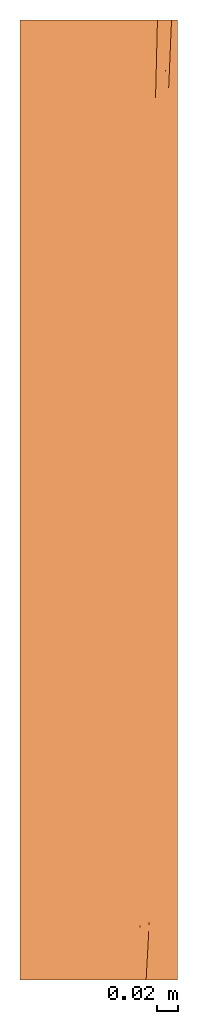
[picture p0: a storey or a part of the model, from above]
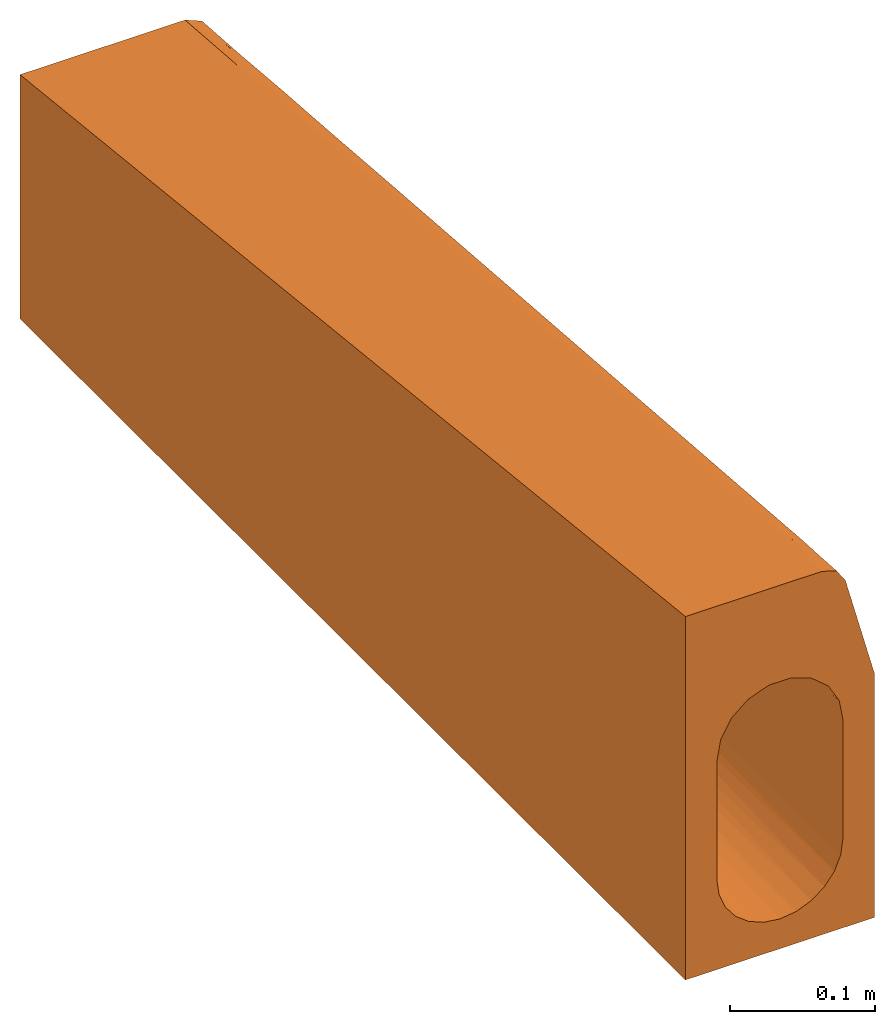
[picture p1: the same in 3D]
Properties of the parts of a building model (IFC2X3)

# File
Description: ViewDefinition [CoordinationView]
File name: 7966 - LH drop kerb - 915mm LG.ifc
Time: 2013-09-12T12:44:50
Written by: Autodesk Revit 2013
Made in: 20120221_2030(x64)

# IfcProject, Project Number
LongName: Project Name; Phase: Project Status

# IfcSite, Default
RefLatitude: 42, 21, 30, 344238; RefLongitude: -71, -3, -35, -194702; RefElevation: 0 mm

# IfcBuilding
Pset_BuildingCommon - NumberOfStoreys: 2
Other - Project Issue Date: Issue Date; Project Status: Project Status; Project Name: Project Name; Client Name: Owner; Project Number: Project Number; Project Address: Enter address here

# IfcBuildingStorey (2)
Constraints - Elevation Base: 0
Graphics - Line Pattern: Center; Color: 0; Symbol at End 2 Default: yes; Symbol at End 1 Default: no; Symbol: M_Level Head - Circle: M_Level Head - Circle; Line Weight: 1
Identity Data - Building Story: yes; Structural: no
Dimensions - Computation Height: 0 mm
Name | LongName = Name | Elevation (mm) = Constraints, Elevation (mm)
T.O. Fnd. Wall | T.O. Fnd. Wall | -300
Level 1 | Level 1 | 0

# IfcBuildingElementProxy: 7966 - LH drop kerb - 915mm LG, Civil-Drainage-Channel-ACO-KerbDrain-HB305 - PART 1:7966 - LH drop kerb - 915mm LG:7966 - LH drop kerb - 915mm LG:255899
In: T.O. Fnd. Wall
Material: ACO Polymer Concrete.
Other - CreatedBy: www.aco.co.uk; Revision: 1
Materials and Finishes - End Cap Colour: N/A; Access Cover/Frame Colour: N/A; Connection Pipe Material Colour: N/A; Channel Colour: Grey; Access Cover/Frame Material: N/A; Channel Material: Vienite® Synthetic Resin Concrete; Access Cover/Frame Finish: N/A; Connection Pipe Material: N/A; End Cap Material: N/A
Dimensions - Volume: 22703438 mm3; Staright Void Depth: -180 mm; Void_Width: 150 mm; Void_Length: 915 mm; I/O Endcap Void depth: 6000 mm
Phasing - Phase Created: Phase 1
Constraints - Moves With Nearby Elements: no; Level: Level: Level 1
Pset_BuildingElementProxyCommon - Reference: 7966 - LH drop kerb - 915mm LG
Identity Data - Assembly Description: Rain Water Drainage; Model: ACO KerbDrain HB305; Type Comments: ACO KerbDrain HB305 half battered left-hand drop kerb unit 915mm long; Fax: +44 (0)1462 815895; Manufacturer: ACO Technologies plc - ACO Water Management Division; E-mail Technical: technical@aco.co.uk; Product Page URL: http://www.aco.co.uk/product_detail.php?id=3; Maintenance guidelines: http://www.aco.co.uk/download.php?id=120; URL: www.aco.co.uk; OmniClass Title: Rainwater Removal; Telephone: +44 (0)1462 816666; E-mail Sales: customersupport@aco.co.uk; Cost: 0; Address: ACO Business Park, Hitchin Road, Shefford, Bedfordshire, United Kingdom SG17 5TE; Assembly Code: D2040; Installation guidelines: http://www.aco.co.uk/download.php?id=120; OmniClass Number: 23.70.50.24; Product brochure: http://www.aco.co.uk/download.php?id=120; Price: POA - contact ACO; Product Code: 7966; Model Description: Combined kerb and drainage system
General - TagNumber: 0.000000; SerialNumber: 0.000000
Construction - KDHB305 - Flush RH dropkerb: no; KDHB305 - Channel unit - 500mm: no; KDHB305 - Closing end cap: no; KDHB305 - Perforated centre stone: no; I/O Pipe: no; KDHB305 - RH drop kerb: no; KDHB305 - Flush LH dropkerb: no; KDHB305 - LH Inlet/Outlet end cap: no; KDHB305 - Access Unit: no; KDHB305 - Channel unit - 1000mm: no; KDHB305 - Blind unit: no; KDHB305 - Centre stone: no; KDHB305 - Channel unit - 250mm: no; KDHB305 - LH drop kerb: yes; KDHB305 - RH Inlet/outlet end cap: no; KDHB305 - Drainable centre stone: no
Data - Product Standard: BS EN 1433:2002, CE marked, Kitemarked; Hydraulic Performance: http://www.aco.co.uk/download.php?id=120; Drainage Slot Intake area: N/A; Installation - Concrete Grade: Refer to brochure; ACO Hydraulic Design Software: http://www.acodesign.co.uk; Product Weight: 49.5 Kg; Load Class: A 15 - D 400; Product Dimensions: 915mm x 150mm x 305/205mm (LxWxH); Connection Pipe O.D: N/A; Invert Depth: 280/180mm; Concrete Surround Volume - Load Class A 15 - D 400 - Concrete Pavement: N/A; Concrete Surround Volume - Load Class A 15 - D 400 - Grass or Asphalt Pavement: N/A; Drainage Slot Width: N/A; Channel C.S.A: 0.02 to 0.008mm²
Green Building Properties - Access Cover/Frame Recycled Material Content: N/A; End Cap Recyclable: N/A; Channel Recycled Material Content: 20% minimum; Access Cover/Frame Recyclable: N/A; End Cap Recycled Material Content: N/A; Channel Recyclable: Fully recyclable

# IfcOpeningElement: Recess (2)
In: Level 1
Constraints - Height Offset From Level: 0 mm; Level: Level: Level 1; Related to Mass: no; Room Bounding: yes
Dimensions - Volume: 21181727206 mm3; Perimeter: 29157.2 mm; Thickness: 400 mm; Area: 53016081 mm2
Structural - Enable Analytical Model: no; Structural: no
Phasing - Phase Created: Phase 1
Construction - Function: 0; Default Thickness: 400 mm
Analytical Properties - Roughness: 1; Absorptance: 0.1
Graphics - Coarse Scale Fill Color: 0

# IfcSlab: Floor:Generic Floor - 400mm, Floor:Generic Floor - 400mm:184025
In: Level 1
PredefinedType: FLOOR; Material: Default Floor 400 mm
Constraints - Height Offset From Level: 0 mm; Level: Level: Level 1; Related to Mass: no; Room Bounding: yes
Dimensions - Volume: 21181727206 mm3; Perimeter: 29157.2 mm; Thickness: 400 mm; Area: 53016081 mm2
Structural - Enable Analytical Model: no; Structural: no
Phasing - Phase Created: Phase 1
Pset_SlabCommon - Reference: Generic Floor - 400mm; IsExternal: no; LoadBearing: yes
Construction - Function: 0; Default Thickness: 400 mm
Analytical Properties - Roughness: 1; Absorptance: 0.1
Graphics - Coarse Scale Fill Color: 0
